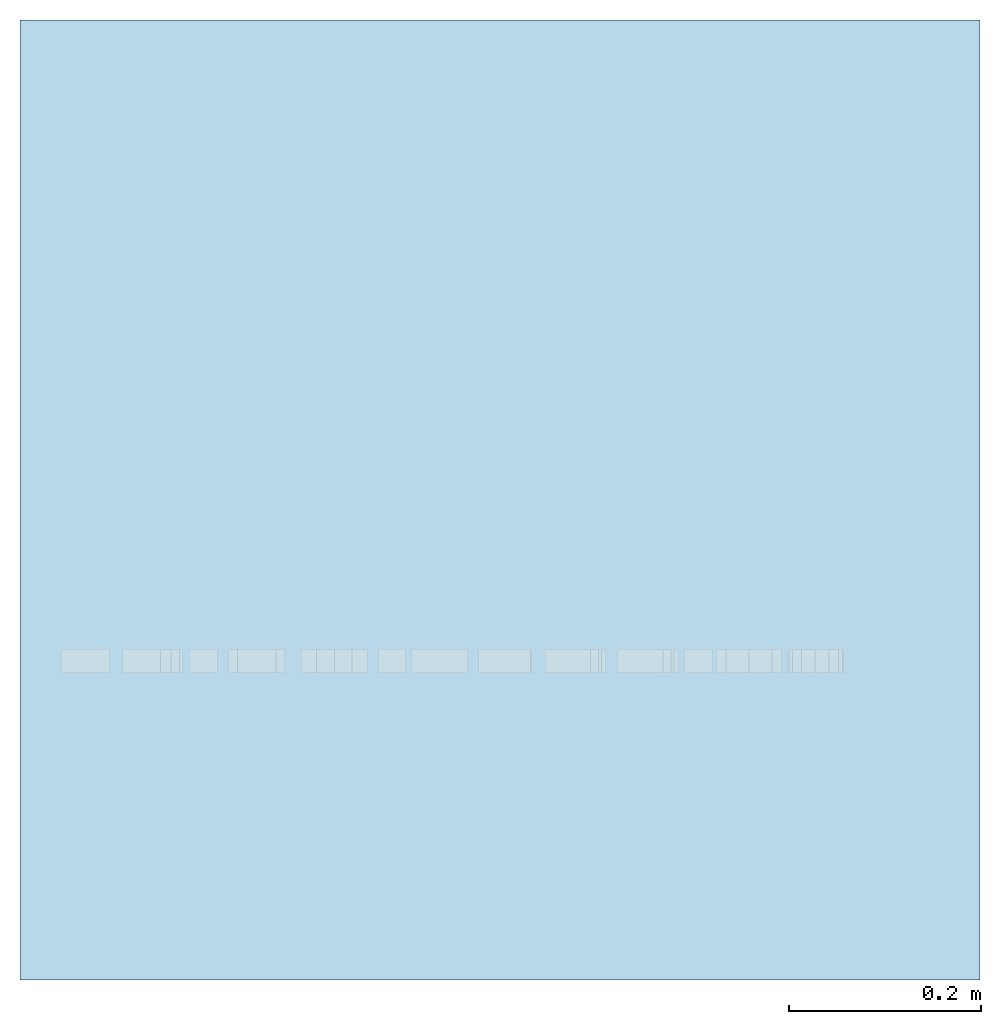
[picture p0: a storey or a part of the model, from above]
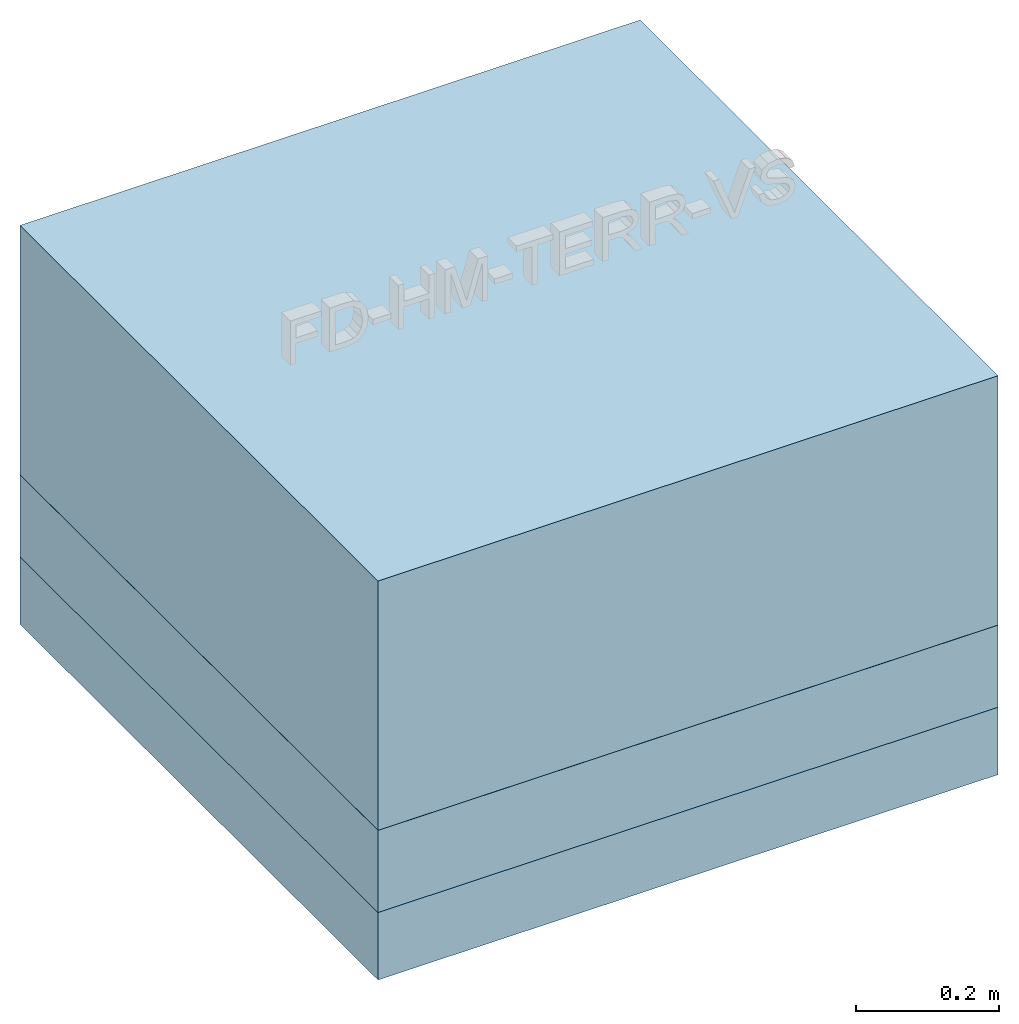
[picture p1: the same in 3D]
Properties of the parts of a building model (IFC4)

# File
Description: ViewDefinition [ReferenceView_V1.2], RevitIdentifiers [VersionGUID: 578dc951-38f8-42b4-9d55-27c226baf1a5, NumberOfSaves: 2], CoordinateReference [CoordinateBase: Gemeinsam genutzte Koordinaten], ExchangeRequirement [Architecture]
File name: 2018_01
Time: 2023-07-05T10:32:27+01:00
Written by: ODA SDAI 23.12
Made in: Autodesk Revit 24.0.5.432 (DEU) - IFC 24.0.5.432

# IfcProject, 2018_01
Phase: Projekt Status

# IfcSite, Default
RefLatitude: 48, 8, 15, 359802; RefLongitude: 11, 34, 47, 783432; RefElevation: 0 m
Pset_SiteCommon - Reference: Projektinformationen

# IfcBuildingElementProxy: Modelltext:075mm Arial, Modelltext:075mm Arial:2510488
In: Default
Type - Pset_BuildingElementProxyCommon - IsExternal: no
Pset_BuildingElementProxyCommon - Reference: 075mm Arial
Pset_EnvironmentalImpactIndicators - Reference: 075mm Arial
Qto_BuildingElementProxyQuantities - NetSurfaceArea: 0.147445 m2; NetVolume: 0.000484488 m3

# IfcElementAssembly: Geschossdecken Baugruppe:fbimSg_Roof_bc_WOD_vis_at_NTR_natuREbuilt_FD-HM-TERR-VS_GK3_68cm, Geschossdecken Baugruppe:fbimSg_Roof_bc_WOD_vis_at_NTR_natuREbuilt_FD-HM-TERR-VS_GK3_68cm:2510510
In: Default
PredefinedType: USERDEFINED; Material: fbim_12400515_AT_025_Vollholz_Bretter_Fichte, fbim_12400520_AT_001_Vollholz_Lattung_Fichte, fbim_14100590_AT_001_Luftschicht, fbim_16051005_AT_225_Estrichbeton_E225, fbim_10200515_AT_001_Schutzvlies, OENORM A6240 Dämmstoff (Hart)
Pset_ElementAssemblyCommon - Reference: fbimSg_Roof_bc_WOD_vis_at_NTR_natuREbuilt_FD-HM-TERR-VS_GK3_68cm; sets with these values: 2

# IfcSlab: Geschossdecke:fbimSg_Floor_dp_INS_vis_at_NTR_natuREbuilt_FD-HM-TERR-VS_GK3_u_11cm, Geschossdecke:fbimSg_Floor_dp_INS_vis_at_NTR_natuREbuilt_FD-HM-TERR-VS_GK3_u_11cm:2510505
In: Default
Type - PredefinedType: FLOOR; Material: fbim_14100590_AT_001_Luftschicht, OENORM A6240 Dämmstoff (Weich), fbim_16101505_AT_Gipsfaserplatte (2)
Type - Pset_SlabCommon - IsExternal: no
Pset_EnvironmentalImpactIndicators - Reference: fbimSg_Floor_dp_INS_vis_at_NTR_natuREbuilt_FD-HM-TERR-VS_GK3_u_11cm; sets with these values: 2
Pset_SlabCommon - PitchAngle: 0 deg; LoadBearing: no; Reference: fbimSg_Floor_dp_INS_vis_at_NTR_natuREbuilt_FD-HM-TERR-VS_GK3_u_11cm
Qto_SlabBaseQuantities - fbim_14100590_AT_001_Luftschicht, Width: 0.04 m; OENORM A6240 Dämmstoff (Weich), Width: 0.05 m; fbim_16101505_AT_Gipsfaserplatte, Width: 0.0125 m; fbim_16101505_AT_Gipsfaserplatte (2), Width: 0.0125 m; Width: 0.115 m; Length: 1 m; Depth: 0.0125 m; Perimeter: 4 m; GrossArea: 1 m2; GrossVolume: 0.0125 m3; NetVolume: 0.115 m3

# IfcSlab: Geschossdecke:fbimSg_Slab_dp_INH_vis_at_NTR_natuREbuilt_FD-HM-TERR-VS_GK3_o_44cm, Geschossdecke:fbimSg_Slab_dp_INH_vis_at_NTR_natuREbuilt_FD-HM-TERR-VS_GK3_o_44cm:2510491
In: Default
Type - PredefinedType: FLOOR; Material: fbim_12400515_AT_025_Vollholz_Bretter_Fichte, fbim_12400520_AT_001_Vollholz_Lattung_Fichte, fbim_14100590_AT_001_Luftschicht, fbim_16051005_AT_225_Estrichbeton_E225, fbim_10200515_AT_001_Schutzvlies, OENORM A6240 Dämmstoff (Hart)
Type - Pset_SlabCommon - IsExternal: no
Pset_EnvironmentalImpactIndicators - Reference: fbimSg_Slab_dp_INH_vis_at_NTR_natuREbuilt_FD-HM-TERR-VS_GK3_o_44cm; sets with these values: 2
Pset_SlabCommon - Reference: fbimSg_Slab_dp_INH_vis_at_NTR_natuREbuilt_FD-HM-TERR-VS_GK3_o_44cm; PitchAngle: 0 deg; LoadBearing: no
Qto_SlabBaseQuantities - fbim_12400515_AT_025_Vollholz_Bretter_Fichte, Width: 0.026 m; fbim_12400520_AT_001_Vollholz_Lattung_Fichte, Width: 0.044 m; fbim_14100590_AT_001_Luftschicht, Width: 0.012 m; fbim_16051005_AT_225_Estrichbeton_E225, Width: 0.04 m; fbim_10200515_AT_001_Schutzvlies, Width: 0.0032 m; OENORM A6240 Dämmstoff (Hart), Width: 0.3 m; Width: 0.4252 m; Length: 1 m; Depth: 0.3 m; Perimeter: 4 m; GrossArea: 1 m2; GrossVolume: 0.3 m3; NetVolume: 0.4252 m3

# IfcSlab: Geschossdecke:fbimSg_Slab_sb_CNR_vis_at_NTR_natuREbuilt_FD-HM-TERR-VS_GK3_k_14, Geschossdecke:fbimSg_Slab_sb_CNR_vis_at_NTR_natuREbuilt_FD-HM-TERR-VS_GK3_k_14:2510498
In: Default
Type - PredefinedType: FLOOR; Material: fbim_12400520_AT_Konstruktionsvollholz_Fichte
Type - Pset_SlabCommon - IsExternal: no
Pset_EnvironmentalImpactIndicators - Reference: fbimSg_Slab_sb_CNR_vis_at_NTR_natuREbuilt_FD-HM-TERR-VS_GK3_k_14; sets with these values: 2
Pset_SlabCommon - PitchAngle: 0 deg; LoadBearing: no; Reference: fbimSg_Slab_sb_CNR_vis_at_NTR_natuREbuilt_FD-HM-TERR-VS_GK3_k_14
Qto_SlabBaseQuantities - Width: 1 m; Length: 1 m; Depth: 0.14 m; Perimeter: 4 m; GrossArea: 1 m2; GrossVolume: 0.14 m3; NetVolume: 0.14 m3
